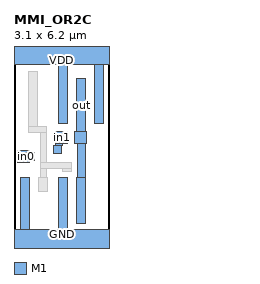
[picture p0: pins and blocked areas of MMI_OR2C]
MACRO MMI_OR2C
	CLASS CORE ;
	FOREIGN MMI_OR2C 0 0 ;
	SIZE 3.1 BY 6.2 ;
	SYMMETRY X Y ;
	SITE CORE1 ;
	PIN out
		DIRECTION output ;
		USE SIGNAL ;
		PORT
			LAYER M1 ;
			RECT 2.05 3.6 2.33 5.325 ;
			LAYER M1 ;
			RECT 1.98 3.22 2.36 3.6 ;
			LAYER M1 ;
			RECT 2.085 2.09 2.325 3.22 ;
			LAYER M1 ;
			RECT 2.05 0.62 2.33 2.09 ;
		END
		AntennaDiffArea 1.2859 ;
	END out
	PIN in1
		DIRECTION input ;
		USE SIGNAL ;
		PORT
			LAYER M1 ;
			RECT 1.36 3.22 1.74 3.6 ;
			LAYER M1 ;
			RECT 1.36 3.155 1.57 3.22 ;
			LAYER M1 ;
			RECT 1.285 3.145 1.57 3.155 ;
			LAYER M1 ;
			RECT 1.285 2.875 1.565 3.145 ;
		END
		AntennaGateArea 0.39 ;
	END in1
	PIN GND
		DIRECTION inout ;
		USE GROUND ;
		PORT
			LAYER M1 ;
			RECT 0.225 0.42 0.505 2.095 ;
			LAYER M1 ;
			RECT 1.46 0.42 1.74 2.09 ;
			LAYER M1 ;
			RECT 0 -0.42 3.1 0.42 ;
		END
	END GND
	PIN VDD
		DIRECTION inout ;
		USE POWER ;
		PORT
			LAYER M1 ;
			RECT 0 5.78 3.1 6.62 ;
			LAYER M1 ;
			RECT 1.46 3.855 1.74 5.78 ;
			LAYER M1 ;
			RECT 2.64 3.855 2.92 5.78 ;
		END
	END VDD
	PIN in0
		DIRECTION input ;
		USE SIGNAL ;
		PORT
			LAYER M1 ;
			RECT 0.12 2.93 0.5 2.98 ;
			LAYER M1 ;
			RECT 0.12 2.65 0.655 2.93 ;
			LAYER M1 ;
			RECT 0.12 2.6 0.5 2.65 ;
		END
		AntennaGateArea 0.39 ;
	END in0
	OBS
		LAYER M1 ;
		RECT 0.485 3.76 0.765 5.58 ;
		LAYER M1 ;
		RECT 0.485 3.57 1.06 3.76 ;
		LAYER M1 ;
		RECT 0.865 2.58 1.06 3.57 ;
		LAYER M1 ;
		RECT 0.865 2.39 1.86 2.58 ;
		LAYER M1 ;
		RECT 0.865 2.095 1.06 2.39 ;
		LAYER M1 ;
		RECT 1.58 2.3 1.86 2.39 ;
		LAYER M1 ;
		RECT 0.815 1.645 1.095 2.095 ;
	END
END MMI_OR2C
